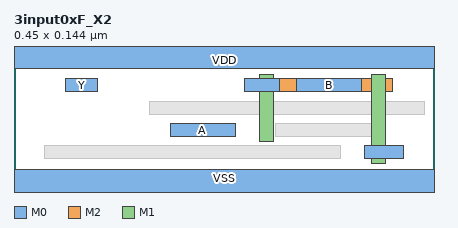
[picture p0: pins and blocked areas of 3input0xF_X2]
MACRO 3input0xF_X2
  CLASS CORE ;
  ORIGIN 0 0 ;
  FOREIGN 3input0xF_X2 0 0 ;
  SIZE 0.4500 BY 0.1440 ;
  SYMMETRY X Y ;
  SITE coresite ;
  PIN A
    DIRECTION INPUT ;
    USE SIGNAL ;
    PORT
      LAYER M0 ;
        RECT 0.1680 0.0530 0.2370 0.0670 ;
    END
  END A
  PIN B
    DIRECTION INPUT ;
    USE SIGNAL ;
    PORT
      LAYER M0 ;
        RECT 0.3030 0.1010 0.3720 0.1150 ;
    END
  END B
  PIN C
    DIRECTION INPUT ;
    USE SIGNAL ;
    PORT
      LAYER M2 ;
        RECT 0.2580 0.1010 0.4050 0.1150 ;
      LAYER M1 ;
        RECT 0.2625 0.0480 0.2775 0.1200 ;
        RECT 0.3825 0.0240 0.3975 0.1200 ;
      LAYER M0 ;
        RECT 0.3750 0.0290 0.4170 0.0430 ;
        RECT 0.2475 0.1010 0.2850 0.1150 ;
    END
  END C
  PIN Y
    DIRECTION OUTPUT ;
    USE SIGNAL ;
    PORT
      LAYER M0 ;
        RECT 0.0555 0.1010 0.0900 0.1150 ;
    END
  END Y
  PIN VDD
    DIRECTION INOUT ;
    USE POWER ;
    SHAPE ABUTMENT ;
    PORT
      LAYER M0 ;
        RECT 0.0000 0.1260 0.4500 0.1620 ;
    END
  END VDD
  PIN VSS
    DIRECTION INOUT ;
    USE GROUND ;
    SHAPE ABUTMENT ;
    PORT
      LAYER M0 ;
        RECT 0.0000 -0.0180 0.4500 0.0180 ;
    END
  END VSS
  OBS
    LAYER V1 ;
      RECT 0.2630 0.1010 0.2770 0.1150 ;
      RECT 0.3830 0.1010 0.3970 0.1150 ;
    LAYER V0 ;
      RECT 0.2630 0.1010 0.2770 0.1150 ;
      RECT 0.3830 0.0290 0.3970 0.0430 ;
    LAYER M0 ;
      RECT 0.0330 0.0290 0.3495 0.0430 ;
      RECT 0.2805 0.0530 0.3945 0.0670 ;
      RECT 0.1455 0.0770 0.4395 0.0910 ;
  END
END 3input0xF_X2
